! (c) 2009  Infineon Technologies AG, Munich
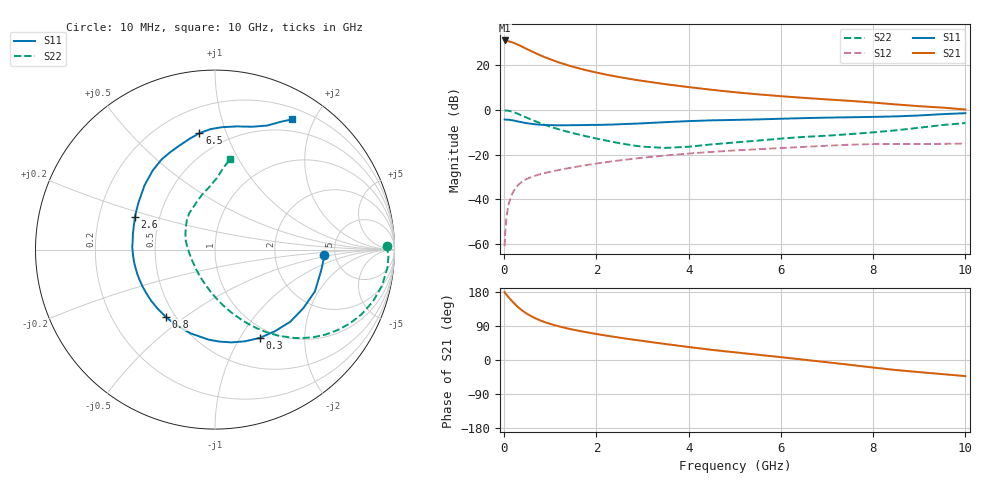
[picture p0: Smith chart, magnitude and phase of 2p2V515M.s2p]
! Infineon Technologies  Discrete & RF Semiconductors
! BFP420
! VCE =  2.5 V,  IC =  15 mA
! Common Emitter S-Parameters:  Nov 2009
# GHz  S  MA  R  50
!  f  S11  S21  S12  S22
! GHz  MAG  ANG  MAG  ANG  MAG  ANG  MAG  ANG
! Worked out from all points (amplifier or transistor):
!   46 points, 10 MHz to 10 GHz, reference 50 ohm
!   highest |S21| = 31.0 dB at 10 MHz (marker M1)
!   |S21| within 3 dB of that: start of sweep to 412.4 MHz
!   unconditionally stable (mu >= 1): 2.023 GHz to end of sweep
!   at 300 MHz: K = 0.26, MSG = 31.4 dB, |S12| = -33.6 dB
!   at 1.7 GHz: K = 0.92, MSG = 21.6 dB, |S12| = -25.0 dB
!   at 10 GHz: K = 1.07, MAG = 6.0 dB, |S12| = -15.1 dB
!   lowest NFmin = 1.06 dB at 900 MHz
!   S11 on the Smith chart (normalised r, x): 10 MHz: 4.10, -0.36; 300 MHz: 0.86, -1.22; 800 MHz: 0.45, -0.43; 2.6 GHz: 0.36, +0.17; 6.5 GHz: 0.36, +0.81; 10 GHz: 0.34, +1.71
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0.01  0.6103 -2.6  35.61 179.0  0.0009 75.4  0.9577 1.3
0.02  0.6088 -4.4  34.75 176.8  0.0016 85.1  0.9671 -2.1
0.05  0.6025 -11.5  34.55 172.3  0.0041 86.7  0.9661 -5.9
0.1  0.6035 -22.7  34.03 165.1  0.008 80.0  0.952 -12.2
0.15  0.5905 -33.6  32.97 158.1  0.0116 75.6  0.9266 -18.1
0.2  0.5807 -43.9  31.67 151.6  0.015 72.1  0.8935 -23.7
0.25  0.5639 -53.9  30.11 145.3  0.018 68.6  0.8567 -28.7
0.3  0.5515 -63.2  28.65 139.7  0.0208 65.5  0.8165 -33.4
0.4  0.5252 -79.8  25.58 129.9  0.0252 60.2  0.7368 -41.4
0.5  0.5028 -94.1  22.73 121.7  0.0289 56.6  0.6631 -48.0
0.6  0.4861 -106.4  20.26 114.6  0.0319 54.0  0.5988 -53.4
0.8  0.4646 -126.0  16.32 103.7  0.0369 51.0  0.4965 -62.0
1  0.4559 -141.2  13.49 95.3  0.0413 49.5  0.4211 -69.0
1.2  0.4533 -153.1  11.4 88.4  0.0456 48.6  0.3639 -75.2
1.7  0.4574 -175.1  8.088 75.2  0.0565 47.0  0.2682 -89.1
2.6  0.4822 157.6  5.18 57.1  0.0764 42.2  0.173 -118.3
3.5  0.5319 137.5  3.75 42.1  0.0957 35.7  0.1413 -158.9
5.5  0.6127 108.8  2.226 13.9  0.1322 19.1  0.2061 142.2
6.5  0.6547 97.6  1.855 0.8  0.1492 10.6  0.2491 125.2
7  0.6715 92.2  1.715 -5.9  0.1582 6.0  0.2651 117.3
8.5  0.7154 73.1  1.322 -26.5  0.1724 -10.5  0.35 95.2
10  0.8442 59.3  1.02 -42.6  0.1761 -21.4  0.5092 80.7
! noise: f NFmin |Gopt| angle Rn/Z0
0.9  1.06  0.09  -152  0.13
1.8  1.36  0.18  -147  0.12
2.4  1.49  0.17  -148  0.14
3  1.53  0.25  -138  0.14
4  1.67  0.38  -119  0.2
5  2.14  0.44  -103  0.32
6  2.48  0.5  -88  0.47
